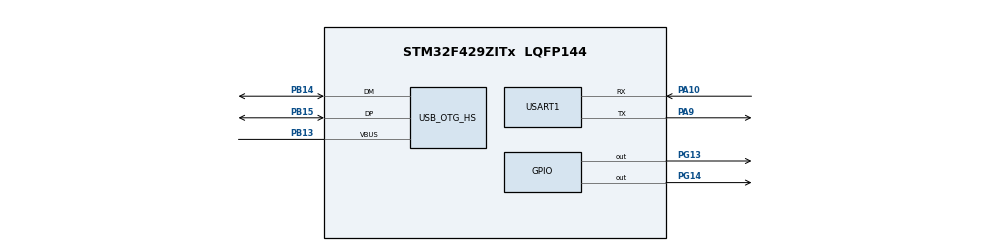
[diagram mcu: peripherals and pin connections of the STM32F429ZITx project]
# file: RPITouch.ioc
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Mcu.Family=STM32F4
Mcu.Name=STM32F429ZITx
Mcu.Package=LQFP144
NVIC.OTG_HS_IRQn=true\:0\:0\:false\:false\:true\:false
NVIC.PriorityGroup=NVIC_PRIORITYGROUP_4
PA10.Mode=Asynchronous
PA10.Signal=USART1_RX
PA13.Mode=Trace_Asynchronous_SW
PA13.Signal=SYS_JTMS-SWDIO
PA14.Mode=Trace_Asynchronous_SW
PA14.Signal=SYS_JTCK-SWCLK
PA9.Mode=Asynchronous
PA9.Signal=USART1_TX
PB13.Mode=Activate_VBUS_FS
PB13.Signal=USB_OTG_HS_VBUS
PB14.Mode=Host_FS
PB14.Signal=USB_OTG_HS_DM
PB15.Mode=Host_FS
PB15.Signal=USB_OTG_HS_DP
PB3.Mode=Trace_Asynchronous_SW
PB3.Signal=SYS_JTDO-SWO
PG13.Signal=GPIO_Output
PG14.Signal=GPIO_Output
PH0/OSC_IN.Mode=HSE-External-Oscillator
PH0/OSC_IN.Signal=RCC_OSC_IN
PH1/OSC_OUT.Mode=HSE-External-Oscillator
PH1/OSC_OUT.Signal=RCC_OSC_OUT
ProjectManager.HeapSize=0x200
ProjectManager.StackSize=0x400
ProjectManager.TargetToolchain=TrueSTUDIO
RCC.48MHZClocksFreq_Value=48000000
RCC.AHBCLKDivider=RCC_SYSCLK_DIV4
RCC.AHBFreq_Value=30000000
RCC.APB1Freq_Value=30000000
RCC.APB1TimFreq_Value=30000000
RCC.APB2Freq_Value=30000000
RCC.APB2TimFreq_Value=30000000
RCC.CortexFreq_Value=30000000
RCC.HCLKFreq_Value=30000000
RCC.HSE_VALUE=8000000
RCC.HSI_VALUE=16000000
RCC.LSE_VALUE=32768
RCC.PLLM=4
RCC.PLLN=120
RCC.PLLQ=5
RCC.SYSCLKFreq_VALUE=120000000
RCC.SYSCLKSource=RCC_SYSCLKSOURCE_PLLCLK
RCC.VCOOutputFreq_Value=240000000
USART1.VirtualMode=VM_ASYNC
USB_HOST.USBH_HandleTypeDef-HID_HS=hUsbHostHS
USB_HOST.VirtualModeHS=Hid
USB_OTG_HS.VirtualMode-Host_FS=Host_FS
VP_USB_HOST_VS_USB_HOST_HID_HS.Mode=HID_HS
board=custom

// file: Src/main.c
/**
  ******************************************************************************
  * @file           : main.c
  * @brief          : Main program body
  ******************************************************************************
  * This notice applies to any and all portions of this file
  * that are not between comment pairs USER CODE BEGIN and
  * USER CODE END. Other portions of this file, whether
  * inserted by the user or by software development tools
  * are owned by their respective copyright owners.
  *
  * Copyright (c) 2020 STMicroelectronics International N.V.
  * All rights reserved.
  *
  * Redistribution and use in source and binary forms, with or without
  * modification, are permitted, provided that the following conditions are met:
  *
  * 1. Redistribution of source code must retain the above copyright notice,
  *    this list of conditions and the following disclaimer.
  * 2. Redistributions in binary form must reproduce the above copyright notice,
  *    this list of conditions and the following disclaimer in the documentation
  *    and/or other materials provided with the distribution.
  * 3. Neither the name of STMicroelectronics nor the names of other
  *    contributors to this software may be used to endorse or promote products
  *    derived from this software without specific written permission.
  * 4. This software, including modifications and/or derivative works of this
  *    software, must execute solely and exclusively on microcontroller or
  *    microprocessor devices manufactured by or for STMicroelectronics.
  * 5. Redistribution and use of this software other than as permitted under
  *    this license is void and will automatically terminate your rights under
  *    this license.
  *
  * THIS SOFTWARE IS PROVIDED BY STMICROELECTRONICS AND CONTRIBUTORS "AS IS"
  * AND ANY EXPRESS, IMPLIED OR STATUTORY WARRANTIES, INCLUDING, BUT NOT
  * LIMITED TO, THE IMPLIED WARRANTIES OF MERCHANTABILITY, FITNESS FOR A
  * PARTICULAR PURPOSE AND NON-INFRINGEMENT OF THIRD PARTY INTELLECTUAL PROPERTY
  * RIGHTS ARE DISCLAIMED TO THE FULLEST EXTENT PERMITTED BY LAW. IN NO EVENT
  * SHALL STMICROELECTRONICS OR CONTRIBUTORS BE LIABLE FOR ANY DIRECT, INDIRECT,
  * INCIDENTAL, SPECIAL, EXEMPLARY, OR CONSEQUENTIAL DAMAGES (INCLUDING, BUT NOT
  * LIMITED TO, PROCUREMENT OF SUBSTITUTE GOODS OR SERVICES; LOSS OF USE, DATA,
  * OR PROFITS; OR BUSINESS INTERRUPTION) HOWEVER CAUSED AND ON ANY THEORY OF
  * LIABILITY, WHETHER IN CONTRACT, STRICT LIABILITY, OR TORT (INCLUDING
  * NEGLIGENCE OR OTHERWISE) ARISING IN ANY WAY OUT OF THE USE OF THIS SOFTWARE,
  * EVEN IF ADVISED OF THE POSSIBILITY OF SUCH DAMAGE.
  *
  ******************************************************************************
  */
#include "main.h"
#include "stm32f4xx_hal.h"
#include "usb_host.h"
#include "retarget.h"

UART_HandleTypeDef huart1;

/* USER CODE BEGIN PV */
/* Private variables ---------------------------------------------------------*/

/* USER CODE END PV */

void SystemClock_Config(void);
static void MX_GPIO_Init(void);
static void MX_USART1_UART_Init(void);
void MX_USB_HOST_Process(void);

int main(void)
{

  /* MCU Configuration----------------------------------------------------------*/

  /* Reset of all peripherals, Initializes the Flash interface and the Systick. */
  HAL_Init();

  /* Configure the system clock */
  SystemClock_Config();

  /* Initialize all configured peripherals */
  MX_GPIO_Init();
  MX_USART1_UART_Init();
  MX_USB_HOST_Init();

  //
  uint32_t lastTick = HAL_GetTick();
  int on = 0;

  /* Infinite loop */
  while (1)
  {
    MX_USB_HOST_Process();

  /* USER CODE BEGIN 3 */
    HAL_GPIO_WritePin(GPIOG, GPIO_PIN_13, on ? GPIO_PIN_RESET : GPIO_PIN_SET);
	//HAL_GPIO_WritePin(GPIOG, GPIO_PIN_14, on ? GPIO_PIN_SET : GPIO_PIN_RESET);

	if (HAL_GetTick() - lastTick > 200)
	{
		static int i = 0;

		lastTick = HAL_GetTick();
		on = 1 - on;

		if (++i == 10)
		{
			i = 0;
			printf("!");
		}
	}

  }
  /* USER CODE END 3 */

}

void SystemClock_Config(void)
{

  RCC_OscInitTypeDef RCC_OscInitStruct;
  RCC_ClkInitTypeDef RCC_ClkInitStruct;

    /**Configure the main internal regulator output voltage
    */
  __HAL_RCC_PWR_CLK_ENABLE();

  __HAL_PWR_VOLTAGESCALING_CONFIG(PWR_REGULATOR_VOLTAGE_SCALE3);

    /**Initializes the CPU, AHB and APB busses clocks
    */
  RCC_OscInitStruct.OscillatorType = RCC_OSCILLATORTYPE_HSE;
  RCC_OscInitStruct.HSEState = RCC_HSE_ON;
  RCC_OscInitStruct.PLL.PLLState = RCC_PLL_ON;
  RCC_OscInitStruct.PLL.PLLSource = RCC_PLLSOURCE_HSE;
  RCC_OscInitStruct.PLL.PLLM = 4;
  RCC_OscInitStruct.PLL.PLLN = 72;
  RCC_OscInitStruct.PLL.PLLP = RCC_PLLP_DIV2;
  RCC_OscInitStruct.PLL.PLLQ = 3;
  if (HAL_RCC_OscConfig(&RCC_OscInitStruct) != HAL_OK)
  {
    _Error_Handler(__FILE__, __LINE__);
  }

    /**Initializes the CPU, AHB and APB busses clocks
    */
  RCC_ClkInitStruct.ClockType = RCC_CLOCKTYPE_HCLK|RCC_CLOCKTYPE_SYSCLK
                              |RCC_CLOCKTYPE_PCLK1|RCC_CLOCKTYPE_PCLK2;
  RCC_ClkInitStruct.SYSCLKSource = RCC_SYSCLKSOURCE_PLLCLK;
  RCC_ClkInitStruct.AHBCLKDivider = RCC_SYSCLK_DIV1;
  RCC_ClkInitStruct.APB1CLKDivider = RCC_HCLK_DIV2;
  RCC_ClkInitStruct.APB2CLKDivider = RCC_HCLK_DIV1;

  if (HAL_RCC_ClockConfig(&RCC_ClkInitStruct, FLASH_LATENCY_2) != HAL_OK)
  {
    _Error_Handler(__FILE__, __LINE__);
  }

    /**Configure the Systick interrupt time
    */
  HAL_SYSTICK_Config(HAL_RCC_GetHCLKFreq()/1000);

    /**Configure the Systick
    */
  HAL_SYSTICK_CLKSourceConfig(SYSTICK_CLKSOURCE_HCLK);

  /* SysTick_IRQn interrupt configuration */
  HAL_NVIC_SetPriority(SysTick_IRQn, 0, 0);
}

/* USART1 init function */
static void MX_USART1_UART_Init(void)
{

  huart1.Instance = USART1;
  huart1.Init.BaudRate = 115200;
  huart1.Init.WordLength = UART_WORDLENGTH_8B;
  huart1.Init.StopBits = UART_STOPBITS_1;
  huart1.Init.Parity = UART_PARITY_NONE;
  huart1.Init.Mode = UART_MODE_TX_RX;
  huart1.Init.HwFlowCtl = UART_HWCONTROL_NONE;
  huart1.Init.OverSampling = UART_OVERSAMPLING_16;

  if (HAL_UART_Init(&huart1) != HAL_OK)
  {
    _Error_Handler(__FILE__, __LINE__);
  }

  RetargetInit(&huart1);
}

/** Configure pins as
        * Analog
        * Input
        * Output
        * EVENT_OUT
        * EXTI
*/
static void MX_GPIO_Init(void)
{
  GPIO_InitTypeDef GPIO_InitStruct;

  /* GPIO Ports Clock Enable */
  __HAL_RCC_GPIOA_CLK_ENABLE();
  __HAL_RCC_GPIOB_CLK_ENABLE();
  __HAL_RCC_GPIOC_CLK_ENABLE();
  __HAL_RCC_GPIOG_CLK_ENABLE();
  __HAL_RCC_GPIOH_CLK_ENABLE();

  /*Configure GPIO pin Output Level */
  HAL_GPIO_WritePin(GPIOG, GPIO_PIN_13|GPIO_PIN_14, GPIO_PIN_RESET);

  /*Configure GPIO pins : PG13 PG14 */
  GPIO_InitStruct.Pin = GPIO_PIN_13|GPIO_PIN_14;
  GPIO_InitStruct.Mode = GPIO_MODE_OUTPUT_PP;
  GPIO_InitStruct.Pull = GPIO_NOPULL;
  GPIO_InitStruct.Speed = GPIO_SPEED_FREQ_LOW;
  HAL_GPIO_Init(GPIOG, &GPIO_InitStruct);
}

void _Error_Handler(char *file, int line)
{
  while(1)
  {
  }
}

/************************ (C) COPYRIGHT STMicroelectronics *****END OF FILE****/
